VERSION 5.7 ;
  NOWIREEXTENSIONATPIN ON ;
  DIVIDERCHAR "/" ;
  BUSBITCHARS "[]" ;
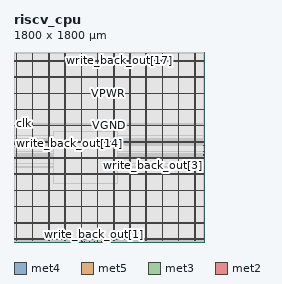
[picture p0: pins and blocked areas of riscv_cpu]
MACRO riscv_cpu
  CLASS BLOCK ;
  FOREIGN riscv_cpu ;
  ORIGIN 0.000 0.000 ;
  SIZE 1800.000 BY 1800.000 ;
  PIN VGND
    DIRECTION INOUT ;
    USE GROUND ;
    PORT
      LAYER met4 ;
        RECT 24.340 10.640 25.940 1787.280 ;
    END
    PORT
      LAYER met4 ;
        RECT 177.940 10.640 179.540 1787.280 ;
    END
    PORT
      LAYER met4 ;
        RECT 331.540 10.640 333.140 1787.280 ;
    END
    PORT
      LAYER met4 ;
        RECT 485.140 10.640 486.740 1787.280 ;
    END
    PORT
      LAYER met4 ;
        RECT 638.740 10.640 640.340 1787.280 ;
    END
    PORT
      LAYER met4 ;
        RECT 792.340 10.640 793.940 1787.280 ;
    END
    PORT
      LAYER met4 ;
        RECT 945.940 10.640 947.540 1787.280 ;
    END
    PORT
      LAYER met4 ;
        RECT 1099.540 10.640 1101.140 1787.280 ;
    END
    PORT
      LAYER met4 ;
        RECT 1253.140 10.640 1254.740 1787.280 ;
    END
    PORT
      LAYER met4 ;
        RECT 1406.740 10.640 1408.340 1787.280 ;
    END
    PORT
      LAYER met4 ;
        RECT 1560.340 10.640 1561.940 1787.280 ;
    END
    PORT
      LAYER met4 ;
        RECT 1713.940 10.640 1715.540 1787.280 ;
    END
    PORT
      LAYER met5 ;
        RECT 5.280 30.030 1794.700 31.630 ;
    END
    PORT
      LAYER met5 ;
        RECT 5.280 183.210 1794.700 184.810 ;
    END
    PORT
      LAYER met5 ;
        RECT 5.280 336.390 1794.700 337.990 ;
    END
    PORT
      LAYER met5 ;
        RECT 5.280 489.570 1794.700 491.170 ;
    END
    PORT
      LAYER met5 ;
        RECT 5.280 642.750 1794.700 644.350 ;
    END
    PORT
      LAYER met5 ;
        RECT 5.280 795.930 1794.700 797.530 ;
    END
    PORT
      LAYER met5 ;
        RECT 5.280 949.110 1794.700 950.710 ;
    END
    PORT
      LAYER met5 ;
        RECT 5.280 1102.290 1794.700 1103.890 ;
    END
    PORT
      LAYER met5 ;
        RECT 5.280 1255.470 1794.700 1257.070 ;
    END
    PORT
      LAYER met5 ;
        RECT 5.280 1408.650 1794.700 1410.250 ;
    END
    PORT
      LAYER met5 ;
        RECT 5.280 1561.830 1794.700 1563.430 ;
    END
    PORT
      LAYER met5 ;
        RECT 5.280 1715.010 1794.700 1716.610 ;
    END
  END VGND
  PIN VPWR
    DIRECTION INOUT ;
    USE POWER ;
    PORT
      LAYER met4 ;
        RECT 21.040 10.640 22.640 1787.280 ;
    END
    PORT
      LAYER met4 ;
        RECT 174.640 10.640 176.240 1787.280 ;
    END
    PORT
      LAYER met4 ;
        RECT 328.240 10.640 329.840 1787.280 ;
    END
    PORT
      LAYER met4 ;
        RECT 481.840 10.640 483.440 1787.280 ;
    END
    PORT
      LAYER met4 ;
        RECT 635.440 10.640 637.040 1787.280 ;
    END
    PORT
      LAYER met4 ;
        RECT 789.040 10.640 790.640 1787.280 ;
    END
    PORT
      LAYER met4 ;
        RECT 942.640 10.640 944.240 1787.280 ;
    END
    PORT
      LAYER met4 ;
        RECT 1096.240 10.640 1097.840 1787.280 ;
    END
    PORT
      LAYER met4 ;
        RECT 1249.840 10.640 1251.440 1787.280 ;
    END
    PORT
      LAYER met4 ;
        RECT 1403.440 10.640 1405.040 1787.280 ;
    END
    PORT
      LAYER met4 ;
        RECT 1557.040 10.640 1558.640 1787.280 ;
    END
    PORT
      LAYER met4 ;
        RECT 1710.640 10.640 1712.240 1787.280 ;
    END
    PORT
      LAYER met5 ;
        RECT 5.280 26.730 1794.700 28.330 ;
    END
    PORT
      LAYER met5 ;
        RECT 5.280 179.910 1794.700 181.510 ;
    END
    PORT
      LAYER met5 ;
        RECT 5.280 333.090 1794.700 334.690 ;
    END
    PORT
      LAYER met5 ;
        RECT 5.280 486.270 1794.700 487.870 ;
    END
    PORT
      LAYER met5 ;
        RECT 5.280 639.450 1794.700 641.050 ;
    END
    PORT
      LAYER met5 ;
        RECT 5.280 792.630 1794.700 794.230 ;
    END
    PORT
      LAYER met5 ;
        RECT 5.280 945.810 1794.700 947.410 ;
    END
    PORT
      LAYER met5 ;
        RECT 5.280 1098.990 1794.700 1100.590 ;
    END
    PORT
      LAYER met5 ;
        RECT 5.280 1252.170 1794.700 1253.770 ;
    END
    PORT
      LAYER met5 ;
        RECT 5.280 1405.350 1794.700 1406.950 ;
    END
    PORT
      LAYER met5 ;
        RECT 5.280 1558.530 1794.700 1560.130 ;
    END
    PORT
      LAYER met5 ;
        RECT 5.280 1711.710 1794.700 1713.310 ;
    END
  END VPWR
  PIN clk
    DIRECTION INPUT ;
    USE SIGNAL ;
    ANTENNAGATEAREA 0.852000 ;
    PORT
      LAYER met3 ;
        RECT 0.000 1118.640 4.000 1119.240 ;
    END
  END clk
  PIN rst
    DIRECTION INPUT ;
    USE SIGNAL ;
    ANTENNAGATEAREA 0.990000 ;
    PORT
      LAYER met2 ;
        RECT 917.790 0.000 918.070 4.000 ;
    END
  END rst
  PIN write_back_out[0]
    DIRECTION OUTPUT ;
    USE SIGNAL ;
    ANTENNADIFFAREA 0.340600 ;
    PORT
      LAYER met3 ;
        RECT 0.000 799.040 4.000 799.640 ;
    END
  END write_back_out[0]
  PIN write_back_out[10]
    DIRECTION OUTPUT ;
    USE SIGNAL ;
    ANTENNADIFFAREA 0.340600 ;
    PORT
      LAYER met3 ;
        RECT 0.000 979.240 4.000 979.840 ;
    END
  END write_back_out[10]
  PIN write_back_out[11]
    DIRECTION OUTPUT ;
    USE SIGNAL ;
    ANTENNADIFFAREA 0.340600 ;
    PORT
      LAYER met3 ;
        RECT 0.000 839.840 4.000 840.440 ;
    END
  END write_back_out[11]
  PIN write_back_out[12]
    DIRECTION OUTPUT ;
    USE SIGNAL ;
    ANTENNADIFFAREA 0.340600 ;
    PORT
      LAYER met2 ;
        RECT 969.310 1796.000 969.590 1800.000 ;
    END
  END write_back_out[12]
  PIN write_back_out[13]
    DIRECTION OUTPUT ;
    USE SIGNAL ;
    ANTENNADIFFAREA 0.340600 ;
    PORT
      LAYER met3 ;
        RECT 0.000 1115.240 4.000 1115.840 ;
    END
  END write_back_out[13]
  PIN write_back_out[14]
    DIRECTION OUTPUT ;
    USE SIGNAL ;
    ANTENNADIFFAREA 0.340600 ;
    PORT
      LAYER met3 ;
        RECT 0.000 1006.440 4.000 1007.040 ;
    END
  END write_back_out[14]
  PIN write_back_out[15]
    DIRECTION OUTPUT ;
    USE SIGNAL ;
    ANTENNADIFFAREA 0.340600 ;
    PORT
      LAYER met3 ;
        RECT 0.000 1105.040 4.000 1105.640 ;
    END
  END write_back_out[15]
  PIN write_back_out[16]
    DIRECTION OUTPUT ;
    USE SIGNAL ;
    ANTENNADIFFAREA 0.340600 ;
    PORT
      LAYER met3 ;
        RECT 0.000 856.840 4.000 857.440 ;
    END
  END write_back_out[16]
  PIN write_back_out[17]
    DIRECTION OUTPUT ;
    USE SIGNAL ;
    ANTENNADIFFAREA 0.340600 ;
    PORT
      LAYER met2 ;
        RECT 1001.510 1796.000 1001.790 1800.000 ;
    END
  END write_back_out[17]
  PIN write_back_out[18]
    DIRECTION OUTPUT ;
    USE SIGNAL ;
    ANTENNADIFFAREA 0.340600 ;
    PORT
      LAYER met3 ;
        RECT 0.000 809.240 4.000 809.840 ;
    END
  END write_back_out[18]
  PIN write_back_out[19]
    DIRECTION OUTPUT ;
    USE SIGNAL ;
    ANTENNADIFFAREA 0.340600 ;
    PORT
      LAYER met2 ;
        RECT 930.670 1796.000 930.950 1800.000 ;
    END
  END write_back_out[19]
  PIN write_back_out[1]
    DIRECTION OUTPUT ;
    USE SIGNAL ;
    ANTENNADIFFAREA 0.340600 ;
    PORT
      LAYER met2 ;
        RECT 760.010 0.000 760.290 4.000 ;
    END
  END write_back_out[1]
  PIN write_back_out[20]
    DIRECTION OUTPUT ;
    USE SIGNAL ;
    ANTENNADIFFAREA 0.340600 ;
    PORT
      LAYER met3 ;
        RECT 0.000 965.640 4.000 966.240 ;
    END
  END write_back_out[20]
  PIN write_back_out[21]
    DIRECTION OUTPUT ;
    USE SIGNAL ;
    ANTENNADIFFAREA 0.340600 ;
    PORT
      LAYER met2 ;
        RECT 933.890 1796.000 934.170 1800.000 ;
    END
  END write_back_out[21]
  PIN write_back_out[22]
    DIRECTION OUTPUT ;
    USE SIGNAL ;
    ANTENNADIFFAREA 0.340600 ;
    PORT
      LAYER met3 ;
        RECT 1796.000 860.240 1800.000 860.840 ;
    END
  END write_back_out[22]
  PIN write_back_out[23]
    DIRECTION OUTPUT ;
    USE SIGNAL ;
    ANTENNADIFFAREA 0.340600 ;
    PORT
      LAYER met2 ;
        RECT 824.410 0.000 824.690 4.000 ;
    END
  END write_back_out[23]
  PIN write_back_out[24]
    DIRECTION OUTPUT ;
    USE SIGNAL ;
    ANTENNADIFFAREA 0.340600 ;
    PORT
      LAYER met3 ;
        RECT 1796.000 914.640 1800.000 915.240 ;
    END
  END write_back_out[24]
  PIN write_back_out[25]
    DIRECTION OUTPUT ;
    USE SIGNAL ;
    ANTENNADIFFAREA 0.340600 ;
    PORT
      LAYER met2 ;
        RECT 1107.770 1796.000 1108.050 1800.000 ;
    END
  END write_back_out[25]
  PIN write_back_out[26]
    DIRECTION OUTPUT ;
    USE SIGNAL ;
    ANTENNADIFFAREA 0.340600 ;
    PORT
      LAYER met2 ;
        RECT 1104.550 1796.000 1104.830 1800.000 ;
    END
  END write_back_out[26]
  PIN write_back_out[27]
    DIRECTION OUTPUT ;
    USE SIGNAL ;
    ANTENNADIFFAREA 0.340600 ;
    PORT
      LAYER met2 ;
        RECT 1082.010 1796.000 1082.290 1800.000 ;
    END
  END write_back_out[27]
  PIN write_back_out[28]
    DIRECTION OUTPUT ;
    USE SIGNAL ;
    ANTENNADIFFAREA 0.340600 ;
    PORT
      LAYER met3 ;
        RECT 0.000 931.640 4.000 932.240 ;
    END
  END write_back_out[28]
  PIN write_back_out[29]
    DIRECTION OUTPUT ;
    USE SIGNAL ;
    ANTENNADIFFAREA 0.340600 ;
    PORT
      LAYER met2 ;
        RECT 1094.890 1796.000 1095.170 1800.000 ;
    END
  END write_back_out[29]
  PIN write_back_out[2]
    DIRECTION OUTPUT ;
    USE SIGNAL ;
    ANTENNADIFFAREA 0.340600 ;
    PORT
      LAYER met3 ;
        RECT 0.000 741.240 4.000 741.840 ;
    END
  END write_back_out[2]
  PIN write_back_out[30]
    DIRECTION OUTPUT ;
    USE SIGNAL ;
    ANTENNADIFFAREA 0.340600 ;
    PORT
      LAYER met3 ;
        RECT 1796.000 829.640 1800.000 830.240 ;
    END
  END write_back_out[30]
  PIN write_back_out[31]
    DIRECTION OUTPUT ;
    USE SIGNAL ;
    ANTENNADIFFAREA 0.340600 ;
    PORT
      LAYER met3 ;
        RECT 1796.000 816.040 1800.000 816.640 ;
    END
  END write_back_out[31]
  PIN write_back_out[3]
    DIRECTION OUTPUT ;
    USE SIGNAL ;
    ANTENNADIFFAREA 0.340600 ;
    PORT
      LAYER met3 ;
        RECT 1796.000 802.440 1800.000 803.040 ;
    END
  END write_back_out[3]
  PIN write_back_out[4]
    DIRECTION OUTPUT ;
    USE SIGNAL ;
    ANTENNADIFFAREA 0.340600 ;
    PORT
      LAYER met2 ;
        RECT 644.090 0.000 644.370 4.000 ;
    END
  END write_back_out[4]
  PIN write_back_out[5]
    DIRECTION OUTPUT ;
    USE SIGNAL ;
    ANTENNADIFFAREA 0.340600 ;
    PORT
      LAYER met3 ;
        RECT 0.000 710.640 4.000 711.240 ;
    END
  END write_back_out[5]
  PIN write_back_out[6]
    DIRECTION OUTPUT ;
    USE SIGNAL ;
    ANTENNADIFFAREA 0.340600 ;
    PORT
      LAYER met2 ;
        RECT 714.930 0.000 715.210 4.000 ;
    END
  END write_back_out[6]
  PIN write_back_out[7]
    DIRECTION OUTPUT ;
    USE SIGNAL ;
    ANTENNADIFFAREA 0.340600 ;
    PORT
      LAYER met3 ;
        RECT 0.000 928.240 4.000 928.840 ;
    END
  END write_back_out[7]
  PIN write_back_out[8]
    DIRECTION OUTPUT ;
    USE SIGNAL ;
    ANTENNADIFFAREA 0.340600 ;
    PORT
      LAYER met2 ;
        RECT 663.410 0.000 663.690 4.000 ;
    END
  END write_back_out[8]
  PIN write_back_out[9]
    DIRECTION OUTPUT ;
    USE SIGNAL ;
    ANTENNADIFFAREA 0.340600 ;
    PORT
      LAYER met2 ;
        RECT 795.430 0.000 795.710 4.000 ;
    END
  END write_back_out[9]
  OBS
      LAYER nwell ;
        RECT 5.330 10.795 1794.650 1787.230 ;
      LAYER li1 ;
        RECT 5.520 10.795 1794.460 1787.125 ;
      LAYER met1 ;
        RECT 4.210 10.640 1794.460 1787.280 ;
      LAYER met2 ;
        RECT 0.550 1795.720 930.390 1796.000 ;
        RECT 931.230 1795.720 933.610 1796.000 ;
        RECT 934.450 1795.720 969.030 1796.000 ;
        RECT 969.870 1795.720 1001.230 1796.000 ;
        RECT 1002.070 1795.720 1081.730 1796.000 ;
        RECT 1082.570 1795.720 1094.610 1796.000 ;
        RECT 1095.450 1795.720 1104.270 1796.000 ;
        RECT 1105.110 1795.720 1107.490 1796.000 ;
        RECT 1108.330 1795.720 1792.990 1796.000 ;
        RECT 0.550 4.280 1792.990 1795.720 ;
        RECT 0.550 4.000 643.810 4.280 ;
        RECT 644.650 4.000 663.130 4.280 ;
        RECT 663.970 4.000 714.650 4.280 ;
        RECT 715.490 4.000 759.730 4.280 ;
        RECT 760.570 4.000 795.150 4.280 ;
        RECT 795.990 4.000 824.130 4.280 ;
        RECT 824.970 4.000 917.510 4.280 ;
        RECT 918.350 4.000 1792.990 4.280 ;
      LAYER met3 ;
        RECT 0.525 1119.640 1796.000 1787.205 ;
        RECT 4.400 1118.240 1796.000 1119.640 ;
        RECT 0.525 1116.240 1796.000 1118.240 ;
        RECT 4.400 1114.840 1796.000 1116.240 ;
        RECT 0.525 1106.040 1796.000 1114.840 ;
        RECT 4.400 1104.640 1796.000 1106.040 ;
        RECT 0.525 1007.440 1796.000 1104.640 ;
        RECT 4.400 1006.040 1796.000 1007.440 ;
        RECT 0.525 980.240 1796.000 1006.040 ;
        RECT 4.400 978.840 1796.000 980.240 ;
        RECT 0.525 966.640 1796.000 978.840 ;
        RECT 4.400 965.240 1796.000 966.640 ;
        RECT 0.525 932.640 1796.000 965.240 ;
        RECT 4.400 931.240 1796.000 932.640 ;
        RECT 0.525 929.240 1796.000 931.240 ;
        RECT 4.400 927.840 1796.000 929.240 ;
        RECT 0.525 915.640 1796.000 927.840 ;
        RECT 0.525 914.240 1795.600 915.640 ;
        RECT 0.525 861.240 1796.000 914.240 ;
        RECT 0.525 859.840 1795.600 861.240 ;
        RECT 0.525 857.840 1796.000 859.840 ;
        RECT 4.400 856.440 1796.000 857.840 ;
        RECT 0.525 840.840 1796.000 856.440 ;
        RECT 4.400 839.440 1796.000 840.840 ;
        RECT 0.525 830.640 1796.000 839.440 ;
        RECT 0.525 829.240 1795.600 830.640 ;
        RECT 0.525 817.040 1796.000 829.240 ;
        RECT 0.525 815.640 1795.600 817.040 ;
        RECT 0.525 810.240 1796.000 815.640 ;
        RECT 4.400 808.840 1796.000 810.240 ;
        RECT 0.525 803.440 1796.000 808.840 ;
        RECT 0.525 802.040 1795.600 803.440 ;
        RECT 0.525 800.040 1796.000 802.040 ;
        RECT 4.400 798.640 1796.000 800.040 ;
        RECT 0.525 742.240 1796.000 798.640 ;
        RECT 4.400 740.840 1796.000 742.240 ;
        RECT 0.525 711.640 1796.000 740.840 ;
        RECT 4.400 710.240 1796.000 711.640 ;
        RECT 0.525 10.715 1796.000 710.240 ;
      LAYER met4 ;
        RECT 371.055 551.655 481.440 1049.065 ;
        RECT 483.840 551.655 484.740 1049.065 ;
        RECT 487.140 551.655 635.040 1049.065 ;
        RECT 637.440 551.655 638.340 1049.065 ;
        RECT 640.740 551.655 788.640 1049.065 ;
        RECT 791.040 551.655 791.940 1049.065 ;
        RECT 794.340 551.655 942.240 1049.065 ;
        RECT 944.640 551.655 945.540 1049.065 ;
        RECT 947.940 551.655 979.505 1049.065 ;
  END
END riscv_cpu
END LIBRARY

